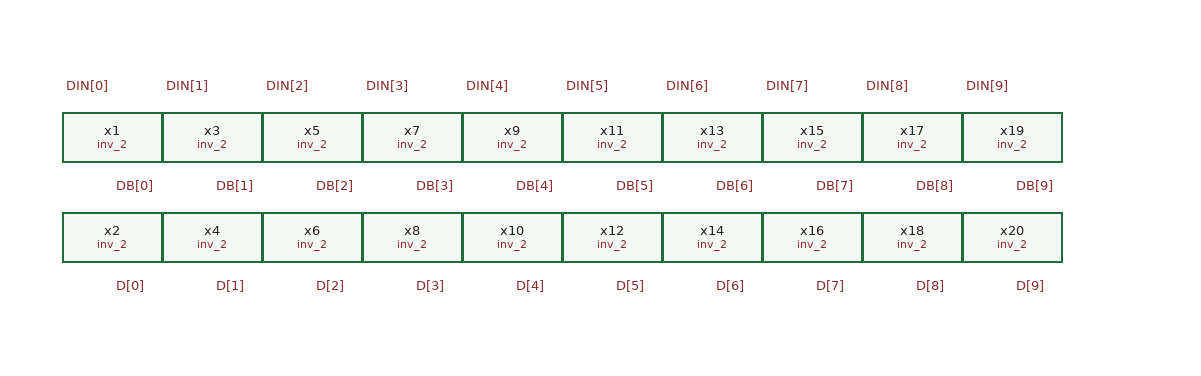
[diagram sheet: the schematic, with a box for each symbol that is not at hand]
v {xschem version=3.4.7RC file_version=1.2}
G {}
K {}
V {}
S {}
E {}
C {sky130_stdcells/inv_2.sym} 270 -280 3 1 {name=x1 VGND=GND VNB=GND VPB=VDD VPWR=VDD prefix=sky130_fd_sc_hd__ }
C {devices/lab_pin.sym} 270 -320 3 1 {name=p3 sig_type=std_logic lab=DIN[0]}
C {devices/lab_pin.sym} 270 -240 2 0 {name=p1 sig_type=std_logic lab=DB[0]}
C {sky130_stdcells/inv_2.sym} 270 -200 3 1 {name=x2 VGND=GND VNB=GND VPB=VDD VPWR=VDD prefix=sky130_fd_sc_hd__ }
C {devices/lab_pin.sym} 270 -160 2 0 {name=p2 sig_type=std_logic lab=D[0]}
C {sky130_stdcells/inv_2.sym} 350 -280 3 1 {name=x3 VGND=GND VNB=GND VPB=VDD VPWR=VDD prefix=sky130_fd_sc_hd__ }
C {devices/lab_pin.sym} 350 -320 3 1 {name=p4 sig_type=std_logic lab=DIN[1]}
C {devices/lab_pin.sym} 350 -240 2 0 {name=p5 sig_type=std_logic lab=DB[1]}
C {sky130_stdcells/inv_2.sym} 350 -200 3 1 {name=x4 VGND=GND VNB=GND VPB=VDD VPWR=VDD prefix=sky130_fd_sc_hd__ }
C {devices/lab_pin.sym} 350 -160 2 0 {name=p6 sig_type=std_logic lab=D[1]}
C {sky130_stdcells/inv_2.sym} 430 -280 3 1 {name=x5 VGND=GND VNB=GND VPB=VDD VPWR=VDD prefix=sky130_fd_sc_hd__ }
C {devices/lab_pin.sym} 430 -320 3 1 {name=p7 sig_type=std_logic lab=DIN[2]}
C {devices/lab_pin.sym} 430 -240 2 0 {name=p8 sig_type=std_logic lab=DB[2]}
C {sky130_stdcells/inv_2.sym} 430 -200 3 1 {name=x6 VGND=GND VNB=GND VPB=VDD VPWR=VDD prefix=sky130_fd_sc_hd__ }
C {devices/lab_pin.sym} 430 -160 2 0 {name=p9 sig_type=std_logic lab=D[2]}
C {sky130_stdcells/inv_2.sym} 510 -280 3 1 {name=x7 VGND=GND VNB=GND VPB=VDD VPWR=VDD prefix=sky130_fd_sc_hd__ }
C {devices/lab_pin.sym} 510 -320 3 1 {name=p10 sig_type=std_logic lab=DIN[3]}
C {devices/lab_pin.sym} 510 -240 2 0 {name=p11 sig_type=std_logic lab=DB[3]}
C {sky130_stdcells/inv_2.sym} 510 -200 3 1 {name=x8 VGND=GND VNB=GND VPB=VDD VPWR=VDD prefix=sky130_fd_sc_hd__ }
C {devices/lab_pin.sym} 510 -160 2 0 {name=p12 sig_type=std_logic lab=D[3]}
C {sky130_stdcells/inv_2.sym} 590 -280 3 1 {name=x9 VGND=GND VNB=GND VPB=VDD VPWR=VDD prefix=sky130_fd_sc_hd__ }
C {devices/lab_pin.sym} 590 -320 3 1 {name=p13 sig_type=std_logic lab=DIN[4]}
C {devices/lab_pin.sym} 590 -240 2 0 {name=p14 sig_type=std_logic lab=DB[4]}
C {sky130_stdcells/inv_2.sym} 590 -200 3 1 {name=x10 VGND=GND VNB=GND VPB=VDD VPWR=VDD prefix=sky130_fd_sc_hd__ }
C {devices/lab_pin.sym} 590 -160 2 0 {name=p15 sig_type=std_logic lab=D[4]}
C {sky130_stdcells/inv_2.sym} 670 -280 3 1 {name=x11 VGND=GND VNB=GND VPB=VDD VPWR=VDD prefix=sky130_fd_sc_hd__ }
C {devices/lab_pin.sym} 670 -320 3 1 {name=p16 sig_type=std_logic lab=DIN[5]}
C {devices/lab_pin.sym} 670 -240 2 0 {name=p17 sig_type=std_logic lab=DB[5]}
C {sky130_stdcells/inv_2.sym} 670 -200 3 1 {name=x12 VGND=GND VNB=GND VPB=VDD VPWR=VDD prefix=sky130_fd_sc_hd__ }
C {devices/lab_pin.sym} 670 -160 2 0 {name=p18 sig_type=std_logic lab=D[5]}
C {sky130_stdcells/inv_2.sym} 750 -280 3 1 {name=x13 VGND=GND VNB=GND VPB=VDD VPWR=VDD prefix=sky130_fd_sc_hd__ }
C {devices/lab_pin.sym} 750 -320 3 1 {name=p19 sig_type=std_logic lab=DIN[6]}
C {devices/lab_pin.sym} 750 -240 2 0 {name=p20 sig_type=std_logic lab=DB[6]}
C {sky130_stdcells/inv_2.sym} 750 -200 3 1 {name=x14 VGND=GND VNB=GND VPB=VDD VPWR=VDD prefix=sky130_fd_sc_hd__ }
C {devices/lab_pin.sym} 750 -160 2 0 {name=p21 sig_type=std_logic lab=D[6]}
C {sky130_stdcells/inv_2.sym} 830 -280 3 1 {name=x15 VGND=GND VNB=GND VPB=VDD VPWR=VDD prefix=sky130_fd_sc_hd__ }
C {devices/lab_pin.sym} 830 -320 3 1 {name=p22 sig_type=std_logic lab=DIN[7]}
C {devices/lab_pin.sym} 830 -240 2 0 {name=p23 sig_type=std_logic lab=DB[7]}
C {sky130_stdcells/inv_2.sym} 830 -200 3 1 {name=x16 VGND=GND VNB=GND VPB=VDD VPWR=VDD prefix=sky130_fd_sc_hd__ }
C {devices/lab_pin.sym} 830 -160 2 0 {name=p24 sig_type=std_logic lab=D[7]}
C {sky130_stdcells/inv_2.sym} 910 -280 3 1 {name=x17 VGND=GND VNB=GND VPB=VDD VPWR=VDD prefix=sky130_fd_sc_hd__ }
C {devices/lab_pin.sym} 910 -320 3 1 {name=p25 sig_type=std_logic lab=DIN[8]}
C {devices/lab_pin.sym} 910 -240 2 0 {name=p26 sig_type=std_logic lab=DB[8]}
C {sky130_stdcells/inv_2.sym} 910 -200 3 1 {name=x18 VGND=GND VNB=GND VPB=VDD VPWR=VDD prefix=sky130_fd_sc_hd__ }
C {devices/lab_pin.sym} 910 -160 2 0 {name=p27 sig_type=std_logic lab=D[8]}
C {sky130_stdcells/inv_2.sym} 990 -280 3 1 {name=x19 VGND=GND VNB=GND VPB=VDD VPWR=VDD prefix=sky130_fd_sc_hd__ }
C {devices/lab_pin.sym} 990 -320 3 1 {name=p28 sig_type=std_logic lab=DIN[9]}
C {devices/lab_pin.sym} 990 -240 2 0 {name=p29 sig_type=std_logic lab=DB[9]}
C {sky130_stdcells/inv_2.sym} 990 -200 3 1 {name=x20 VGND=GND VNB=GND VPB=VDD VPWR=VDD prefix=sky130_fd_sc_hd__ }
C {devices/lab_pin.sym} 990 -160 2 0 {name=p30 sig_type=std_logic lab=D[9]}
